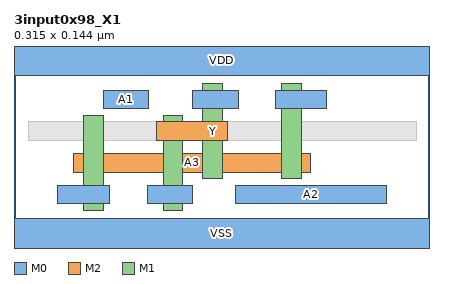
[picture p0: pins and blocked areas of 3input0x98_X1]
MACRO 3input0x98_X1
  CLASS CORE ;
  ORIGIN 0 0 ;
  FOREIGN 3input0x98_X1 0 0 ;
  SIZE 0.3150 BY 0.1440 ;
  SYMMETRY X Y ;
  SITE coresite ;
  PIN A1
    DIRECTION INPUT ;
    USE SIGNAL ;
    PORT
      LAYER M0 ;
        RECT 0.0680 0.1010 0.1020 0.1150 ;
    END
  END A1
  PIN A2
    DIRECTION INPUT ;
    USE SIGNAL ;
    PORT
      LAYER M0 ;
        RECT 0.1680 0.0290 0.2820 0.0430 ;
    END
  END A2
  PIN A3
    DIRECTION INPUT ;
    USE SIGNAL ;
    PORT
      LAYER M2 ;
        RECT 0.0450 0.0530 0.2250 0.0670 ;
      LAYER M1 ;
        RECT 0.0530 0.0240 0.0680 0.0960 ;
        RECT 0.2030 0.0480 0.2180 0.1200 ;
      LAYER M0 ;
        RECT 0.1980 0.1010 0.2370 0.1150 ;
        RECT 0.0330 0.0290 0.0720 0.0430 ;
    END
  END A3
  PIN Y
    DIRECTION OUTPUT ;
    USE SIGNAL ;
    PORT
      LAYER M2 ;
        RECT 0.1080 0.0770 0.1620 0.0910 ;
      LAYER M1 ;
        RECT 0.1130 0.0240 0.1280 0.0960 ;
        RECT 0.1430 0.0480 0.1580 0.1200 ;
      LAYER M0 ;
        RECT 0.1350 0.1010 0.1700 0.1150 ;
        RECT 0.1010 0.0290 0.1350 0.0430 ;
    END
  END Y
  PIN VDD
    DIRECTION INOUT ;
    USE POWER ;
    SHAPE ABUTMENT ;
    PORT
      LAYER M0 ;
        RECT 0.0000 0.1260 0.3150 0.1620 ;
    END
  END VDD
  PIN VSS
    DIRECTION INOUT ;
    USE GROUND ;
    SHAPE ABUTMENT ;
    PORT
      LAYER M0 ;
        RECT 0.0000 -0.0180 0.3150 0.0180 ;
    END
  END VSS
  OBS
    LAYER V1 ;
      RECT 0.0530 0.0530 0.0670 0.0670 ;
      RECT 0.2030 0.0530 0.2170 0.0670 ;
      RECT 0.1130 0.0770 0.1270 0.0910 ;
      RECT 0.1430 0.0770 0.1570 0.0910 ;
    LAYER V0 ;
      RECT 0.0530 0.0290 0.0670 0.0430 ;
      RECT 0.2030 0.1010 0.2170 0.1150 ;
      RECT 0.1130 0.0290 0.1270 0.0430 ;
      RECT 0.1430 0.1010 0.1570 0.1150 ;
    LAYER M0 ;
      RECT 0.0560 0.0530 0.1700 0.0670 ;
      RECT 0.0110 0.0770 0.3050 0.0910 ;
  END
END 3input0x98_X1
